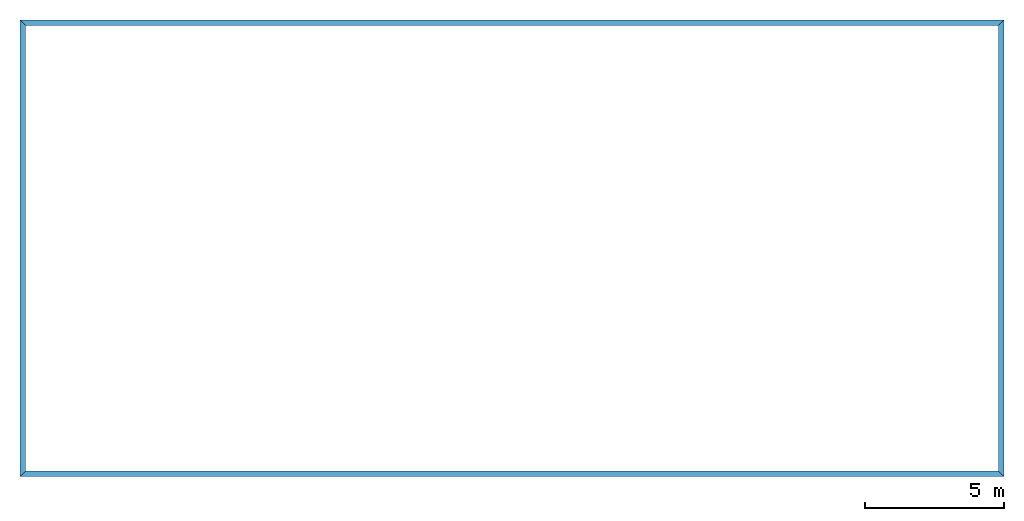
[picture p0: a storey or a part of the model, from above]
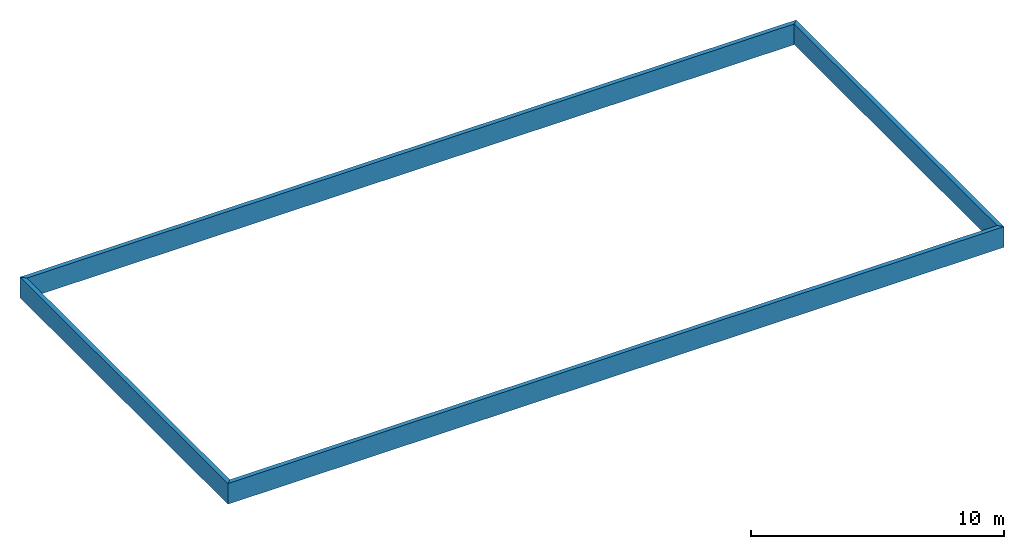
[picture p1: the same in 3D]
Properties of the parts of a building model (IFC2X3)

# File
Description: ViewDefinition [CoordinationView_V2.0], Option [Elements to export: Visible elements (on all stories)], Option [Partial Structure Display: Entire Model], Option [IFC Domain: All], Option [Structural Function: All Elements], Option [Convert Grid elements: On], Option [Convert IFC Annotations and Archicad 2D elements: Off], Option [Convert 2D symbols of Doors and Windows: Off], Option [Export geometries that Participates in Collision Detection only: Off], Option [Split complex elements: Off], Option [Material Preservation: Explode where necessary], Option [Elements in Solid Element Operations: Extruded/revolved], Option [Elements with junctions: Extruded/revolved without junctions], Option [IFC Model position: Survey Point and Project Origin], Option [Curtain Wall export mode: Container Element], Option [Railing export mode: Single Element], Option [Stair export mode: Container Element], Option [Properties To Export: All properties], Option [Space containment: Off], Option [Geometry to type objects: Off], Option [Element Properties: Off], Option [Building Material Properties: Off], Option [Element Parameters: Off], Option [Component Parameters: Off], Option [IFC Base Quantities: Off], Option [Door Window Parameters: On], Option [IFC Space boundaries: Off], Option [Archicad Zone Categories as IFC Space classification data: Off], Option [Element Classifications: Off]
File name: C:\Users\LUCAS\Desktop\FT DCE\IFC\3D PROJET 100.ifc
Time: 2026-07-02T18:41:05
Author: Nom de famille Prénom
Organization: ATELIER D'ARCHITECTURE AIROLDI
Written by: DDS_IFC v3.0
Made in: Graphisoft - Archicad - 28.4.0
Authorization: Nom de famille Prénom

# IfcProject, Construction d'un immeuble de bureaux Agence France Travail
Phase: (provisoire, définitif...)

# IfcSite, Site
RefLatitude: 48, 52, 0, 0; RefLongitude: 2, 20, 0, 0; RefElevation: 149 m

# IfcBuildingStorey (5)
In: Bâtiment
Name | Elevation (m)
R-1 | -3
Toiture | 10.12
Combles | 7.12
RDC | 0
R+1 | 3.56

# IfcBeam: ** COUVERTINE 01 50x5cm 379 x 50 (7)
Material: Métal - Fer
AC_Pset_RenovationAndPhasing - Renovation Status: New
Pset_BeamCommon - IsExternal: no; LoadBearing: yes; Reference: ** COUVERTINE 01 50x5cm 379 x 50
Name | In
3 x PoBA-002 | R+1
4 x PoBA-002 | Combles

# IfcBeam: ** LOGO FT 917 x 1022, PoBA-003
In: R+1
AC_Pset_RenovationAndPhasing - Renovation Status: New
Pset_BeamCommon - IsExternal: no; LoadBearing: yes; Reference: ** LOGO FT 917 x 1022

# IfcBeam: ** LOGO FT petit 448 x 500, PoBA-003
In: R+1
Pset_BeamCommon - IsExternal: no; LoadBearing: yes; Reference: ** LOGO FT petit 448 x 500
AC_Pset_RenovationAndPhasing - Renovation Status: New

# IfcBeam: Acier 50 x 50 (2)
In: Combles
Material: Acier
AC_Pset_RenovationAndPhasing - Renovation Status: New
Pset_BeamCommon - IsExternal: no; LoadBearing: yes; Reference: Acier 50 x 50

# IfcBeam: Aluminium 100 x 150 (8)
In: Toiture
Material: Aluminium
Pset_BeamCommon - IsExternal: no; LoadBearing: yes; Reference: Aluminium 100 x 150
AC_Pset_RenovationAndPhasing - Renovation Status: New

# IfcBeam: Aluminium 100 x 3 (83)
Material: Aluminium
AC_Pset_RenovationAndPhasing - Renovation Status: New
Pset_BeamCommon - IsExternal: no; LoadBearing: yes; Reference: Aluminium 100 x 3
Name | In
4 x PoBA-002 | RDC
79 x PoBA-002 | R+1

# IfcBeam: Aluminium 50 x 50 (3)
In: Combles
Material: Aluminium
AC_Pset_RenovationAndPhasing - Renovation Status: New
Pset_BeamCommon - IsExternal: no; LoadBearing: yes; Reference: Aluminium 50 x 50

# IfcBeam: Aluminium 50 x 75 (10)
In: Toiture
Material: Aluminium
Pset_BeamCommon - IsExternal: no; LoadBearing: yes; Reference: Aluminium 50 x 75
AC_Pset_RenovationAndPhasing - Renovation Status: New

# IfcBeam: Bois massif 80 x 40 (2)
In: R+1
Material: Bois massif
Pset_BeamCommon - IsExternal: no; LoadBearing: yes; Reference: Bois massif 80 x 40
AC_Pset_RenovationAndPhasing - Renovation Status: New

# IfcBeam: Béton 250 x 400 (8)
Material: Béton
AC_Pset_RenovationAndPhasing - Renovation Status: New
Pset_BeamCommon - IsExternal: no; LoadBearing: yes; Reference: Béton 250 x 400
Name | In
6 x PoBA-006 | RDC
2 x PoBA-006 | R+1

# IfcBeam: Béton 250 x 665, PoBA-006
In: RDC
Material: Béton
AC_Pset_RenovationAndPhasing - Renovation Status: New
Pset_BeamCommon - IsExternal: no; LoadBearing: yes; Reference: Béton 250 x 665

# IfcBeam: Métal - Acier 80 x 30, PANNE MULTIBEAM
In: RDC
Material: Métal - Acier
Pset_BeamCommon - IsExternal: no; LoadBearing: yes; Reference: Métal - Acier 80 x 30
AC_Pset_RenovationAndPhasing - Renovation Status: New

# IfcBeam: Métal - Acier 80 x 40 (8)
In: RDC
Material: Métal - Acier
AC_Pset_RenovationAndPhasing - Renovation Status: New
Pset_BeamCommon - IsExternal: no; LoadBearing: yes; Reference: Métal - Acier 80 x 40

# IfcBeam: UAP80 45 x 80 (5)
In: Combles
Material: Acier
AC_Pset_RenovationAndPhasing - Renovation Status: New
Pset_BeamCommon - IsExternal: no; LoadBearing: yes; Reference: UAP80 45 x 80

# IfcBuildingElementPart (288)
Name | In | Material
185 x Acier Galva | RDC | Acier Galva
2 x Finition int - Stratifié | RDC | Finition int - Stratifié
7 x Métal - Zinc | RDC | Métal - Zinc
6 x Métal - Aluminium | RDC | Métal - Aluminium
9 x *MAILLE jacob | RDC | *MAILLE jacob
2 x Finition int - Plaque de plâtre | RDC | Finition int - Plaque de plâtre
Isolation - Laine de verre | RDC | Isolation - Laine de verre
8 x Env. - Sable | R+1 | Env. - Sable
14 x GENERIQUE - ENVIRONNEMENT | R+1 | GENERIQUE - ENVIRONNEMENT
6 x Plastique - PVC | R+1 | Plastique - PVC
8 x Métal - Zinc | R+1 | Métal - Zinc
6 x Env. - Herbe | R+1 | Env. - Herbe
6 x *PLAQUE DE PLATRE - CLOISON | R+1 | *PLAQUE DE PLATRE - CLOISON
3 x *GENERIQUE - ISOLATION INT | R+1 | *GENERIQUE - ISOLATION INT
3 x Isolation - Laine de verre | R+1 | Isolation - Laine de verre
6 x Finition int - Plaque de plâtre | R+1 | Finition int - Plaque de plâtre
3 x Finition int - Stratifié | R+1 | Finition int - Stratifié
3 x Métal - Aluminium | R+1 | Métal - Aluminium
2 x *GENERIQUE - ENDUIT EXT | Combles | *GENERIQUE - ENDUIT EXT
2 x *GENERIQUE - MAÇONNERIE | Combles | *GENERIQUE - MAÇONNERIE
2 x *MÉTAL- BARDAGE | Combles | *MÉTAL- BARDAGE
2 x Finition int - Enduit plâtre | Combles | Finition int - Enduit plâtre
2 x Divers - Vide faux plafond | Combles | Divers - Vide faux plafond

# IfcBuildingElementProxy: IfcBuildingElementProxy (5)
In: RDC
Material: Béton
AC_Pset_RenovationAndPhasing - Renovation Status: New
Name
VOLEE-008
VOLEE-010
PALIER-004
PALIER-003
VOLEE-009

# IfcBuildingElementProxy: Lavabo 27 (4)
AC_Pset_RenovationAndPhasing - Renovation Status: New
Name | In
2 x PLACE STATIONNEMENT PMR | RDC
VIDOIR | RDC
PLACE STATIONNEMENT PMR | R+1

# IfcBuildingElementProxy: Plan multi vasques 27 (2)
AC_Pset_RenovationAndPhasing - Renovation Status: New
Name | In
PLACE STATIONNEMENT PMR | RDC
PLACE STATIONNEMENT PMR | R+1

# IfcBuildingElementProxy: Porte-serviettes 03 27 (3)
AC_Pset_RenovationAndPhasing - Renovation Status: New
Name | In
2 x barre d'appui | RDC
barre d'appui | R+1

# IfcBuildingElementProxy: TAPIS ENCASTRÉ (5)
AC_Pset_RenovationAndPhasing - Renovation Status: New
Name | In
2 x LAVABO | RDC
3 x CLOUS PODO | R+1

# IfcBuildingElementProxy: Type d'escalier, ESC-004
In: RDC
AC_Pset_RenovationAndPhasing - Renovation Status: New

# IfcBuildingElementProxy: Type de garde-corps (5)
In: RDC
Name | Renovation Status
3 x RAMPE-004 | New
RAMPE-003 | Existing
RAMPE-003 | New

# IfcBuildingElementProxy: WC 27 (3)
AC_Pset_RenovationAndPhasing - Renovation Status: New
Name | In
PLACE STATIONNEMENT PMR | RDC
2 x PLACE STATIONNEMENT PMR | R+1

# IfcColumn: Aluminium 100 x 100 (8)
In: Toiture
Material: Aluminium
AC_Pset_RenovationAndPhasing - Renovation Status: New
Pset_ColumnCommon - LoadBearing: yes; Reference: Aluminium 100 x 100

# IfcColumn: Aluminium 100 x 3 (78)
Material: Aluminium
AC_Pset_RenovationAndPhasing - Renovation Status: New
Pset_ColumnCommon - LoadBearing: yes; Reference: Aluminium 100 x 3
Name | In
16 x PotB-005 | RDC
62 x PotB-005 | R+1

# IfcColumn: Aluminium 20 x 50 (3)
In: R+1
Material: Aluminium
AC_Pset_RenovationAndPhasing - Renovation Status: New
Pset_ColumnCommon - LoadBearing: yes; Reference: Aluminium 20 x 50

# IfcColumn: Aluminium 50 x 20 (2)
In: R+1
Material: Aluminium
Pset_ColumnCommon - LoadBearing: yes; Reference: Aluminium 50 x 20
AC_Pset_RenovationAndPhasing - Renovation Status: New

# IfcColumn: Aluminium 50 x 50 (3)
In: R+1
Material: Aluminium
AC_Pset_RenovationAndPhasing - Renovation Status: New
Pset_ColumnCommon - LoadBearing: yes; Reference: Aluminium 50 x 50

# IfcColumn: Bois - Massif 01 40 x 80 (28)
In: R+1
Material: Bois - Massif 01
AC_Pset_RenovationAndPhasing - Renovation Status: New
Pset_ColumnCommon - LoadBearing: yes; Reference: Bois - Massif 01 40 x 80

# IfcColumn: Béton 250 x 250 (16)
Material: Béton
AC_Pset_RenovationAndPhasing - Renovation Status: New
Pset_ColumnCommon - LoadBearing: yes; Reference: Béton 250 x 250
Name | In
8 x PotB-005 | RDC
8 x PotB-005 | R+1

# IfcColumn: Béton 300 x 300, PotB-008
In: R+1
Material: Béton
AC_Pset_RenovationAndPhasing - Renovation Status: New
Pset_ColumnCommon - LoadBearing: yes; Reference: Béton 300 x 300

# IfcColumn: Béton D250 (2)
In: RDC
Material: Béton
AC_Pset_RenovationAndPhasing - Renovation Status: New
Pset_ColumnCommon - LoadBearing: yes; Reference: Béton D250

# IfcColumn: Métal - Acier 20 x 20 (86)
In: RDC
Material: Métal - Acier
AC_Pset_RenovationAndPhasing - Renovation Status: New
Pset_ColumnCommon - LoadBearing: yes; Reference: Métal - Acier 20 x 20

# IfcColumn: Métal - Acier 30 x 80 (6)
In: RDC
Material: Métal - Acier
AC_Pset_RenovationAndPhasing - Renovation Status: New
Pset_ColumnCommon - LoadBearing: yes; Reference: Métal - Acier 30 x 80

# IfcColumn: Métal - Acier 40 x 80 (13)
In: RDC
Material: Métal - Acier
AC_Pset_RenovationAndPhasing - Renovation Status: New
Pset_ColumnCommon - LoadBearing: yes; Reference: Métal - Acier 40 x 80

# IfcCovering: Tôle profilée 27 (67)
Material: Métal - Acier
AC_Pset_RenovationAndPhasing - Renovation Status: New
Name | In
13 x PLACE STATIONNEMENT PMR | RDC
54 x PLACE STATIONNEMENT PMR | R+1

# IfcDiscreteAccessory: Texte 3D 27 (4)
In: R+1
AC_Pset_RenovationAndPhasing - Renovation Status: New

# IfcDiscreteAccessory: Tuyau descente 27 (4)
In: RDC
AC_Pset_RenovationAndPhasing - Renovation Status: New

# IfcDistributionElement: WC pour handicapés 27 (3)
AC_Pset_RenovationAndPhasing - Renovation Status: New
Name | In
2 x WC PMR | RDC
WC PMR | R+1

# IfcDoor: Porte 27 (2)
In: RDC
Type - OperationType: SINGLE_SWING_LEFT; ParameterTakesPrecedence: no; Sizeable: no
Type - Door Lining Properties - LiningDepth: 0.05 m; LiningThickness: 0.05 m; LiningOffset: -0.05 m
Type - Door Panel Properties - Panel 1 - PanelDepth: 0.04 m; PanelOperation: SWINGING; PanelWidth: 1; PanelPosition: MIDDLE
OverallHeight: 2.1 m; OverallWidth: 1 m
Pset_DoorCommon - ThermalTransmittance: 0; IsExternal: no
AC_Pset_RenovationAndPhasing - Renovation Status: New
Name
Pi.05
Pi.04 REI30 + FP

# IfcDoor: Porte 27, Pi.04 REI30
In: RDC
Type - OperationType: SINGLE_SWING_LEFT; ParameterTakesPrecedence: no; Sizeable: no
Type - Door Lining Properties - LiningDepth: 0.05 m; LiningThickness: 0.05 m; LiningOffset: 0 m
Type - Door Panel Properties - Panel 1 - PanelDepth: 0.04 m; PanelOperation: SWINGING; PanelWidth: 1; PanelPosition: MIDDLE
OverallHeight: 2.1 m; OverallWidth: 1 m
Pset_DoorCommon - ThermalTransmittance: 0; IsExternal: no
AC_Pset_RenovationAndPhasing - Renovation Status: New

# IfcDoor: Porte 27 (4)
Type - OperationType: SINGLE_SWING_LEFT; ParameterTakesPrecedence: no; Sizeable: no
Type - Door Lining Properties - LiningDepth: 0.05 m; LiningThickness: 0.05 m; LiningOffset: 0.024 m
Type - Door Panel Properties - Panel 1 - PanelDepth: 0.04 m; PanelOperation: SWINGING; PanelWidth: 1; PanelPosition: MIDDLE
OverallHeight: 2.1 m; OverallWidth: 1 m
Pset_DoorCommon - ThermalTransmittance: 0; IsExternal: no
AC_Pset_RenovationAndPhasing - Renovation Status: New
Name | In
2 x Pi.05 | RDC
2 x Pi.05 | R+1

# IfcDoor: Porte 27, Pi.04 REI30 + FP
In: R+1
Type - OperationType: SINGLE_SWING_LEFT; ParameterTakesPrecedence: no; Sizeable: no
Type - Door Lining Properties - LiningDepth: 0.05 m; LiningThickness: 0.05 m; LiningOffset: 0.05 m
Type - Door Panel Properties - Panel 1 - PanelDepth: 0.04 m; PanelOperation: SWINGING; PanelWidth: 1; PanelPosition: MIDDLE
OverallHeight: 2.1 m; OverallWidth: 1 m
Pset_DoorCommon - ThermalTransmittance: 0; IsExternal: no
AC_Pset_RenovationAndPhasing - Renovation Status: New

# IfcDoor: Porte 27, PE.02
In: RDC
Type - OperationType: SINGLE_SWING_LEFT; ParameterTakesPrecedence: no; Sizeable: no
Type - Door Lining Properties - LiningDepth: 0.12 m; LiningThickness: 0.05 m; LiningOffset: -0.002 m; CasingThickness: 0.05 m; CasingDepth: 0.019 m
Type - Door Panel Properties - Panel 1 - PanelDepth: 0.04 m; PanelOperation: SWINGING; PanelWidth: 1; PanelPosition: MIDDLE
OverallHeight: 2.5 m; OverallWidth: 1.05 m
Pset_DoorCommon - ThermalTransmittance: 0; GlazingAreaFraction: 1.7301; IsExternal: yes
AC_Pset_RenovationAndPhasing - Renovation Status: New

# IfcDoor: Porte 27, PE.03
In: RDC
Type - OperationType: SINGLE_SWING_LEFT; ParameterTakesPrecedence: no; Sizeable: no
Type - Door Lining Properties - LiningDepth: 0.16 m; LiningThickness: 0.05 m; LiningOffset: -0.002 m; CasingThickness: 0.05 m; CasingDepth: 0.019 m
Type - Door Panel Properties - Panel 1 - PanelDepth: 0.04 m; PanelOperation: SWINGING; PanelWidth: 1; PanelPosition: MIDDLE
OverallHeight: 2.5 m; OverallWidth: 1.05 m
Pset_DoorCommon - ThermalTransmittance: 0; GlazingAreaFraction: 1.7301; IsExternal: yes
AC_Pset_RenovationAndPhasing - Renovation Status: New

# IfcDoor: Porte 27 (10)
Type - OperationType: SINGLE_SWING_LEFT; ParameterTakesPrecedence: no; Sizeable: no
Type - Door Lining Properties - LiningThickness: 0.05 m
Type - Door Panel Properties - Panel 1 - PanelDepth: 0.04 m; PanelOperation: SWINGING; PanelWidth: 1; PanelPosition: MIDDLE
OverallHeight: 2.1 m; OverallWidth: 1 m
Pset_DoorCommon - ThermalTransmittance: 0; IsExternal: no
AC_Pset_RenovationAndPhasing - Renovation Status: New
Name | In
2 x Pi.03 | RDC
2 x Pi.01 | RDC
6 x Pi.01 | R+1

# IfcDoor: Porte 27 (2)
Type - OperationType: SINGLE_SWING_RIGHT; ParameterTakesPrecedence: no; Sizeable: no
Type - Door Lining Properties - LiningDepth: 0.05 m; LiningThickness: 0.05 m; LiningOffset: -0.074 m
Type - Door Panel Properties - Panel 1 - PanelDepth: 0.04 m; PanelOperation: SWINGING; PanelWidth: 1; PanelPosition: MIDDLE
OverallHeight: 2.1 m; OverallWidth: 1 m
Pset_DoorCommon - ThermalTransmittance: 0; IsExternal: no
AC_Pset_RenovationAndPhasing - Renovation Status: New
Name | In
Pi.06 | RDC
Pi.06 | R+1

# IfcDoor: Porte 27 (4)
Type - OperationType: SINGLE_SWING_RIGHT; ParameterTakesPrecedence: no; Sizeable: no
Type - Door Lining Properties - LiningDepth: 0.05 m; LiningThickness: 0.05 m; LiningOffset: 0.024 m
Type - Door Panel Properties - Panel 1 - PanelDepth: 0.04 m; PanelOperation: SWINGING; PanelWidth: 1; PanelPosition: MIDDLE
OverallHeight: 2.1 m; OverallWidth: 1 m
Pset_DoorCommon - ThermalTransmittance: 0; IsExternal: no
AC_Pset_RenovationAndPhasing - Renovation Status: New
Name | In
Pi.06 | RDC
Pi.05 | R+1
2 x Pi.06 | R+1

# IfcDoor: Porte 27, Pi.01
In: R+1
Type - OperationType: SINGLE_SWING_RIGHT; ParameterTakesPrecedence: no; Sizeable: no
Type - Door Lining Properties - LiningDepth: 0.05 m; LiningThickness: 0.05 m; LiningOffset: 0.03 m
Type - Door Panel Properties - Panel 1 - PanelDepth: 0.04 m; PanelOperation: SWINGING; PanelWidth: 1; PanelPosition: MIDDLE
OverallHeight: 2.1 m; OverallWidth: 1 m
Pset_DoorCommon - ThermalTransmittance: 0; IsExternal: no
AC_Pset_RenovationAndPhasing - Renovation Status: New

# IfcDoor: Porte 27 (10)
Type - OperationType: SINGLE_SWING_RIGHT; ParameterTakesPrecedence: no; Sizeable: no
Type - Door Lining Properties - LiningThickness: 0.05 m
Type - Door Panel Properties - Panel 1 - PanelDepth: 0.04 m; PanelOperation: SWINGING; PanelWidth: 1; PanelPosition: MIDDLE
OverallHeight: 2.1 m; OverallWidth: 1 m
Pset_DoorCommon - ThermalTransmittance: 0; IsExternal: no
AC_Pset_RenovationAndPhasing - Renovation Status: New
Name | In
5 x Pi.01 | RDC
5 x Pi.01 | R+1

# IfcDoor: Porte avec imposte 27, Pi.01
In: RDC
Type - OperationType: SINGLE_SWING_RIGHT; ParameterTakesPrecedence: no; Sizeable: no
Type - Door Lining Properties - LiningThickness: 0.05 m; TransomThickness: 0.04 m; TransomOffset: 1.99 m
Type - Door Panel Properties - Panel 1 - PanelDepth: 0.04 m; PanelOperation: SWINGING; PanelWidth: 1; PanelPosition: MIDDLE
OverallHeight: 2.6 m; OverallWidth: 1 m
Pset_DoorCommon - ThermalTransmittance: 0; GlazingAreaFraction: 0.4743; IsExternal: no
AC_Pset_RenovationAndPhasing - Renovation Status: New

# IfcDoor: Porte avec tierce vitrée côté 2 27, PE.04
In: R+1
Type - OperationType: SINGLE_SWING_LEFT; ParameterTakesPrecedence: no; Sizeable: no
Type - Door Panel Properties - Panel 1 - PanelDepth: 0.04 m; PanelOperation: SWINGING; PanelWidth: 1; PanelPosition: MIDDLE
OverallHeight: 2.15 m; OverallWidth: 1.4 m
Pset_DoorCommon - ThermalTransmittance: 0; GlazingAreaFraction: 1.92314; IsExternal: yes
AC_Pset_RenovationAndPhasing - Renovation Status: New

# IfcDoor: Porte avec tierce vitrée côté 2 27 (2)
In: R+1
Type - OperationType: SINGLE_SWING_RIGHT; ParameterTakesPrecedence: no; Sizeable: no
Type - Door Panel Properties - Panel 1 - PanelDepth: 0.04 m; PanelOperation: SWINGING; PanelWidth: 1; PanelPosition: MIDDLE
OverallWidth: 1.4 m
Pset_DoorCommon - ThermalTransmittance: 0
AC_Pset_RenovationAndPhasing - Renovation Status: New
Name | OverallHeight (m) | GlazingAreaFraction | IsExternal
Pi.07 | 2.1 | 0.397946 | no
PE.04 | 2.15 | 1.92314 | yes

# IfcDoor: Porte double 27, Pi.03
In: RDC
Type - OperationType: DOUBLE_DOOR_SINGLE_SWING; ParameterTakesPrecedence: no; Sizeable: no
Type - Door Lining Properties - LiningDepth: 0.05 m; LiningThickness: 0.05 m; LiningOffset: -0.05 m
Type - Door Panel Properties - Panel 1 - PanelDepth: 0.04 m; PanelOperation: SWINGING; PanelWidth: 0.397187; PanelPosition: LEFT
Type - Door Panel Properties - Panel 2 - PanelDepth: 0.04 m; PanelOperation: SWINGING; PanelWidth: 0.602813; PanelPosition: RIGHT
OverallHeight: 2.1 m; OverallWidth: 1.563 m
Pset_DoorCommon - ThermalTransmittance: 0; IsExternal: no
AC_Pset_RenovationAndPhasing - Renovation Status: New

# IfcDoor: Porte double 27, Pi.03
In: RDC
Type - OperationType: DOUBLE_DOOR_SINGLE_SWING; ParameterTakesPrecedence: no; Sizeable: no
Type - Door Lining Properties - LiningDepth: 0.05 m; LiningThickness: 0.05 m; LiningOffset: -0.05 m
Type - Door Panel Properties - Panel 1 - PanelDepth: 0.04 m; PanelOperation: SWINGING; PanelWidth: 0.397591; PanelPosition: RIGHT
Type - Door Panel Properties - Panel 2 - PanelDepth: 0.04 m; PanelOperation: SWINGING; PanelWidth: 0.602409; PanelPosition: LEFT
OverallHeight: 2.1 m; OverallWidth: 1.564 m
Pset_DoorCommon - ThermalTransmittance: 0; IsExternal: no
AC_Pset_RenovationAndPhasing - Renovation Status: New

# IfcDoor: Porte double 27, Pi.02
In: RDC
Type - OperationType: DOUBLE_DOOR_SINGLE_SWING; ParameterTakesPrecedence: no; Sizeable: no
Type - Door Lining Properties - LiningDepth: 0.05 m; LiningThickness: 0.05 m; LiningOffset: 0 m
Type - Door Panel Properties - Panel 1 - PanelDepth: 0.04 m; PanelOperation: SWINGING; PanelWidth: 0.370629; PanelPosition: RIGHT
Type - Door Panel Properties - Panel 2 - PanelDepth: 0.04 m; PanelOperation: SWINGING; PanelWidth: 0.629371; PanelPosition: LEFT
OverallHeight: 2.1 m; OverallWidth: 1.5 m
Pset_DoorCommon - ThermalTransmittance: 0; IsExternal: no
AC_Pset_RenovationAndPhasing - Renovation Status: New

# IfcDoor: Porte double 27, Pi.03
In: R+1
Type - OperationType: DOUBLE_DOOR_SINGLE_SWING; ParameterTakesPrecedence: no; Sizeable: no
Type - Door Lining Properties - LiningDepth: 0.05 m; LiningThickness: 0.05 m; LiningOffset: 0.03 m
Type - Door Panel Properties - Panel 1 - PanelDepth: 0.04 m; PanelOperation: SWINGING; PanelWidth: 0.395973; PanelPosition: RIGHT
Type - Door Panel Properties - Panel 2 - PanelDepth: 0.04 m; PanelOperation: SWINGING; PanelWidth: 0.604027; PanelPosition: LEFT
OverallHeight: 2.1 m; OverallWidth: 1.56 m
Pset_DoorCommon - ThermalTransmittance: 0; IsExternal: no
AC_Pset_RenovationAndPhasing - Renovation Status: New

# IfcDoor: Porte double 27, Pi.03
In: R+1
Type - OperationType: DOUBLE_DOOR_SINGLE_SWING; ParameterTakesPrecedence: no; Sizeable: no
Type - Door Lining Properties - LiningDepth: 0.05 m; LiningThickness: 0.05 m; LiningOffset: 0.03 m
Type - Door Panel Properties - Panel 1 - PanelDepth: 0.04 m; PanelOperation: SWINGING; PanelWidth: 0.397591; PanelPosition: LEFT
Type - Door Panel Properties - Panel 2 - PanelDepth: 0.04 m; PanelOperation: SWINGING; PanelWidth: 0.602409; PanelPosition: RIGHT
OverallHeight: 2.1 m; OverallWidth: 1.564 m
Pset_DoorCommon - ThermalTransmittance: 0; IsExternal: no
AC_Pset_RenovationAndPhasing - Renovation Status: New

# IfcDoor: Porte double 27, PE.01
In: RDC
Type - OperationType: DOUBLE_DOOR_SINGLE_SWING; ParameterTakesPrecedence: no; Sizeable: no
Type - Door Lining Properties - LiningDepth: 0.16 m; LiningThickness: 0.05 m; LiningOffset: 0.168 m; CasingThickness: 0.05 m; CasingDepth: 0.07 m
Type - Door Panel Properties - Panel 1 - PanelDepth: 0.04 m; PanelOperation: SWINGING; PanelWidth: 0.324324; PanelPosition: RIGHT
Type - Door Panel Properties - Panel 2 - PanelDepth: 0.04 m; PanelOperation: SWINGING; PanelWidth: 0.675676; PanelPosition: LEFT
OverallHeight: 2.5 m; OverallWidth: 1.6 m
Pset_DoorCommon - ThermalTransmittance: 0; GlazingAreaFraction: 2.628; IsExternal: yes
AC_Pset_RenovationAndPhasing - Renovation Status: New

# IfcDoor: Porte double avec 2 fixes latéraux, imposte 27, PC.01a
In: RDC
Type - OperationType: USERDEFINED; ParameterTakesPrecedence: no; Sizeable: no
OverallHeight: 2.6 m; OverallWidth: 2.86158 m
Pset_DoorCommon - ThermalTransmittance: 0; GlazingAreaFraction: 5.61587; IsExternal: no
AC_Pset_RenovationAndPhasing - Renovation Status: New

# IfcFurnishingElement: Armoire 02 27 (2)
In: R+1
AC_Pset_RenovationAndPhasing - Renovation Status: New

# IfcFurnishingElement: Bac à terre 27, PLACE STATIONNEMENT PMR
In: R+1
AC_Pset_RenovationAndPhasing - Renovation Status: New

# IfcFurnishingElement: Canapé 01 27, WC PMR
In: R+1
AC_Pset_RenovationAndPhasing - Renovation Status: New

# IfcFurnishingElement: Casiers 27, WC PMR
In: R+1
AC_Pset_RenovationAndPhasing - Renovation Status: New

# IfcFurnishingElement: Chaise de conférence 1 27 (51)
AC_Pset_RenovationAndPhasing - Renovation Status: New
Name | In
39 x PLACE STATIONNEMENT PMR | RDC
12 x PLACE STATIONNEMENT PMR | R+1

# IfcFurnishingElement: Meuble bas bloc 27 (5)
In: R+1
AC_Pset_RenovationAndPhasing - Renovation Status: New

# IfcFurnishingElement: Poste de travail de bureau unique 27 (45)
AC_Pset_RenovationAndPhasing - Renovation Status: New
Name | In
18 x PLACE STATIONNEMENT PMR | RDC
27 x PLACE STATIONNEMENT PMR | R+1

# IfcFurnishingElement: Réfrigérateur haut 27 (3)
In: R+1
AC_Pset_RenovationAndPhasing - Renovation Status: New

# IfcFurnishingElement: Table haute rectangulaire 27 (2)
In: RDC
AC_Pset_RenovationAndPhasing - Renovation Status: New

# IfcFurnishingElement: Table haute ronde 27 (12)
AC_Pset_RenovationAndPhasing - Renovation Status: New
Name | In
2 x PLACE STATIONNEMENT PMR | RDC
10 x PLACE STATIONNEMENT PMR | R+1

# IfcSlab: *Dalle portée hourdi isolé + finition 220, DC_BA_Isol-005
In: RDC
Type - PredefinedType: FLOOR
Material: *FINITION SOL INT - sol souple 0.02 m, *GENERIQUE - MAÇONNERIE 0.05 m, *GENERIQUE - ISOLATION PLANCHER 0.15 m
Pset_SlabCommon - IsExternal: no; LoadBearing: yes
AC_Pset_RenovationAndPhasing - Renovation Status: New

# IfcSlab: *MAILLE jacob 30, DC_BA_Isol-005
In: R+1
Type - PredefinedType: FLOOR
Material: *MAILLE jacob 0.03 m
AC_Pset_RenovationAndPhasing - Renovation Status: New
Pset_SlabCommon - IsExternal: no; LoadBearing: yes

# IfcSlab: *Plafond 1/2 STIL 61 (8)
Type - PredefinedType: FLOOR
Material: *OSSATURE PLACO 0.048 m, *PLAQUE DE PLATRE - PLAFOND 0.013 m
AC_Pset_RenovationAndPhasing - Renovation Status: New
Pset_SlabCommon - IsExternal: no; LoadBearing: no
Name | In
Plafond métallique acoustique perforé | RDC
4 x Plafond acoustique démontable | RDC
Plafond acoustique démontable 1ère volée escalier | RDC
Plafond acoustique démontable WC public RDC | RDC
Plafond acoustique démontable | R+1

# IfcSlab: *Plancher béton+CHAPE+FINITION 290, DC_BA_Isol-004
In: RDC
Type - PredefinedType: FLOOR
Material: *FINITION SOL INT - sol souple 0.02 m, *CHAPE 0.07 m, *GENERIQUE - MAÇONNERIE 0.2 m
AC_Pset_RenovationAndPhasing - Renovation Status: Existing
Pset_SlabCommon - IsExternal: no; LoadBearing: yes

# IfcSlab: *Plancher béton+FINITION 220 (2)
Type - PredefinedType: FLOOR
Material: *FINITION SOL INT - sol souple 0.02 m, *GENERIQUE - MAÇONNERIE 0.2 m
Pset_SlabCommon - IsExternal: no; LoadBearing: yes
AC_Pset_RenovationAndPhasing - Renovation Status: New
Name | In
DC_BA_Isol-005 | R+1
DC_BA_Isol-005 | Combles

# IfcSlab: *Toiture MEMBRANE PVC 355, Toit-08
In: Toiture
Type - PredefinedType: ROOF
Material: *ÉTANCHÉITÉ 0.015 m, *GENERIQUE - ISOLATION PLANCHER 0.14 m, Béton 0.2 m
Pset_SlabCommon - IsExternal: yes; LoadBearing: no
AC_Pset_RenovationAndPhasing - Renovation Status: New

# IfcSlab: *Toiture TERRASSE ETANCHÉE graviers 335, DC_BA_Isol-005
In: R+1
Type - PredefinedType: FLOOR
Material: *GRAVIERS 0.05 m, *ÉTANCHÉITÉ 0.015 m, *GENERIQUE - ISOLATION PLANCHER 0.07 m, Béton 0.2 m
AC_Pset_RenovationAndPhasing - Renovation Status: New
Pset_SlabCommon - IsExternal: no; LoadBearing: yes

# IfcSlab: *Toiture TERRASSE ETANCHÉE sur plots 485, DC_BA_Isol-005
In: R+1
Type - PredefinedType: FLOOR
Material: Béton préfabriqué 0.05 m, Vide faux plafond 0.15 m, *ÉTANCHÉITÉ 0.015 m, *GENERIQUE - ISOLATION PLANCHER 0.07 m, Béton 0.2 m
Pset_SlabCommon - IsExternal: no; LoadBearing: yes
AC_Pset_RenovationAndPhasing - Renovation Status: New

# IfcSlab: *Toiture TUILES 150 (7)
Type - PredefinedType: ROOF
Material: *TUILES, *BOIS - LATTAGE OU LITEAUX, *BOIS SOLIVAGE
AC_Pset_RenovationAndPhasing - Renovation Status: Existing
Pset_SlabCommon - IsExternal: yes; LoadBearing: no
Name | In
Toit-07 | R+1
2 x Toit-07 | Combles
3 x Toit-07 | Toiture
Toit-08 | Toiture

# IfcSlab: Asphalte 200, DC_BA_Isol-005
In: RDC
Type - PredefinedType: FLOOR
Material: Asphalte 0.2 m
AC_Pset_RenovationAndPhasing - Renovation Status: New
Pset_SlabCommon - IsExternal: no; LoadBearing: yes

# IfcSlab: Eau 1500, Bassin rétention EP
In: RDC
Type - PredefinedType: FLOOR
Material: Eau 1.5 m
Pset_SlabCommon - IsExternal: no; LoadBearing: yes
AC_Pset_RenovationAndPhasing - Renovation Status: New

# IfcSlab: Eau 200, Bassin rétention EP
In: RDC
Type - PredefinedType: FLOOR
Material: Eau 0.2 m
AC_Pset_RenovationAndPhasing - Renovation Status: New
Pset_SlabCommon - IsExternal: no; LoadBearing: yes

# IfcSlab: Eau 870, Bassin rétention EP
In: RDC
Type - PredefinedType: FLOOR
Material: Eau 0.87 m
AC_Pset_RenovationAndPhasing - Renovation Status: New
Pset_SlabCommon - IsExternal: no; LoadBearing: yes

# IfcSlab: Plastique 50 (2)
In: R+1
Type - PredefinedType: ROOF
Material: Plastique 0.0498779 m
AC_Pset_RenovationAndPhasing - Renovation Status: New
Pset_SlabCommon - IsExternal: yes; LoadBearing: no

# IfcTransportElement: Ascenseur 27, WC PMR
In: RDC
AC_Pset_RenovationAndPhasing - Renovation Status: New

# IfcWall: *Cloison 72 74 (4)
AC_Pset_RenovationAndPhasing - Renovation Status: New
Name | In | IsExternal = LoadBearing
Cloisons ép. 72mm | RDC | yes
3 x Cloisons ép. 72mm | R+1 | no

# IfcWall: *Cloison 98 100 (3)
In: R+1
AC_Pset_RenovationAndPhasing - Renovation Status: New
Pset_WallCommon - IsExternal: no; LoadBearing: no

# IfcWall: *MACONNERIE BARDAGE METAL Acrotère 318 (2)
In: Combles
AC_Pset_RenovationAndPhasing - Renovation Status: New
Pset_WallCommon - IsExternal: yes; LoadBearing: yes

# IfcWall: *PLAQUE DE PLATRE - CLOISON 13, Plaque de plâtre collée
In: R+1
Material: *PLAQUE DE PLATRE - CLOISON
AC_Pset_RenovationAndPhasing - Renovation Status: New
Pset_WallCommon - IsExternal: no; LoadBearing: no

# IfcWallStandardCase: *Cloison 72 74 (36)
Material: Finition int - Plaque de plâtre 0.013 m, Isolation - Laine de verre 0.048 m, Finition int - Plaque de plâtre 0.013 m
AC_Pset_RenovationAndPhasing - Renovation Status: New
Name | In | IsExternal = LoadBearing
24 x Cloisons ép. 72mm | RDC | yes
Cloisons ép. 72mm | RDC | no
11 x Cloisons ép. 72mm | R+1 | no

# IfcWallStandardCase: *Cloison 98 100 (11)
Material: *PLAQUE DE PLATRE - CLOISON 0.026 m, *GENERIQUE - ISOLATION INT 0.048 m, *PLAQUE DE PLATRE - CLOISON 0.026 m
AC_Pset_RenovationAndPhasing - Renovation Status: New
Name | In | IsExternal = LoadBearing
7 x Cloison ép.10 - CF1h | RDC | no
Cloison ép.10 - CF1h | RDC | yes
3 x Cloison ép.10 - CF1h | R+1 | no

# IfcWallStandardCase: *GENERIQUE - MAÇONNERIE 200 (2)
Material: *GENERIQUE - MAÇONNERIE 0.2 m
AC_Pset_RenovationAndPhasing - Renovation Status: New
Pset_WallCommon - IsExternal: yes; LoadBearing: yes
Name | In
MC_AGL_Ext-063 | RDC
MC_AGL_Ext-063 | R+1

# IfcWallStandardCase: *GENERIQUE - MAÇONNERIE 5 (62)
In: R+1
Material: *GENERIQUE - MAÇONNERIE 0.005 m
AC_Pset_RenovationAndPhasing - Renovation Status: New
Pset_WallCommon - IsExternal: yes; LoadBearing: yes

# IfcWallStandardCase: *MACONNERIE BARDAGE METAL Acrotère 318 (5)
Material: *MÉTAL- BARDAGE 0.04 m, Divers - Vide faux plafond 0.05 m, Finition int - Enduit plâtre 0.01 m, *GENERIQUE - MAÇONNERIE 0.2 m, *GENERIQUE - ENDUIT EXT 0.018 m
AC_Pset_RenovationAndPhasing - Renovation Status: New
Pset_WallCommon - IsExternal: yes; LoadBearing: yes
Name | In
3 x Mur maçonné + ITI + véture métallique | R+1
2 x Mur maçonné + ITI + véture métallique | Combles

# IfcWallStandardCase: *MACONNERIE ITI BARDAGE METAL 478 (8)
Material: *MÉTAL- BARDAGE 0.04 m, Divers - Vide faux plafond 0.05 m, Finition int - Enduit plâtre 0.01 m, *GENERIQUE - MAÇONNERIE 0.2 m, Finition int - Enduit plâtre 0.01 m, Vide pour liteaux 0.01 m, *GENERIQUE - ISOLATION PLANCHER 0.14 m, *PLAQUE DE PLATRE - DOUBLAGE 0.018 m
AC_Pset_RenovationAndPhasing - Renovation Status: New
Pset_WallCommon - IsExternal: yes; LoadBearing: yes
Name | In
4 x Mur maçonné + ITI + véture métallique | RDC
4 x Mur maçonné + ITI + véture métallique | R+1

# IfcWallStandardCase: *MAILLE jacob 20 (2)
In: R+1
Material: *MAILLE jacob 0.02 m
AC_Pset_RenovationAndPhasing - Renovation Status: New
Pset_WallCommon - IsExternal: no; LoadBearing: no

# IfcWallStandardCase: *Mur ENDUIT 1 face 220 (12)
Material: *GENERIQUE - ENDUIT EXT 0.02 m, *GENERIQUE - MAÇONNERIE 0.2 m
Pset_WallCommon - IsExternal: yes; LoadBearing: yes
Name | In | Renovation Status
MC_AGL_Ext-052 | RDC | Existing
MC_AGL_Ext-053 | RDC | Existing
MC_AGL_Ext-051 | RDC | Existing
MC_AGL_Ext-054 | RDC | Existing
MC_AGL_Ext-060 | RDC | New
MC_AGL_Ext-063 | RDC | New
MC_AGL_Ext-061 | RDC | New
MC_AGL_Ext-062 | RDC | New
MC_AGL_Ext-058 | R+1 | New
MC_AGL_Ext-060 | R+1 | New
MC_AGL_Ext-059 | R+1 | New
MC_AGL_Ext-061 | R+1 | New

# IfcWallStandardCase: *Mur MITI 36 353 (154)
Material: *GENERIQUE - ENDUIT EXT 0.02 m, *GENERIQUE - MAÇONNERIE 0.2 m, *GENERIQUE - ISOLATION INT 0.12 m, *PLAQUE DE PLATRE - DOUBLAGE 0.013 m
AC_Pset_RenovationAndPhasing - Renovation Status: Existing
Pset_WallCommon - IsExternal: yes; LoadBearing: yes
Name | In
MC_AGL_Ext-017 | RDC
MC_AGL_Ext-018 | RDC
MC_AGL_Ext-019 | RDC
MC_AGL_Ext-020 | RDC
MC_AGL_Ext-021 | RDC
MC_AGL_Ext-022 | RDC
MC_AGL_Ext-023 | RDC
MC_AGL_Ext-024 | RDC
MC_AGL_Ext-025 | RDC
MC_AGL_Ext-026 | RDC
MC_AGL_Ext-027 | RDC
MC_AGL_Ext-028 | RDC
MC_AGL_Ext-029 | RDC
MC_AGL_Ext-030 | RDC
MC_AGL_Ext-031 | RDC
MC_AGL_Ext-032 | RDC
MC_AGL_Ext-033 | RDC
MC_AGL_Ext-034 | RDC
MC_AGL_Ext-037 | RDC
MC_AGL_Ext-036 | RDC
MC_AGL_Ext-035 | RDC
MC_AGL_Ext-039 | RDC
MC_AGL_Ext-040 | RDC
MC_AGL_Ext-041 | RDC
MC_AGL_Ext-042 | RDC
MC_AGL_Ext-043 | RDC
MC_AGL_Ext-044 | RDC
2 x MC_AGL_Ext-045 | RDC
2 x MC_AGL_Ext-046 | RDC
2 x MC_AGL_Ext-047 | RDC
2 x MC_AGL_Ext-048 | RDC
2 x MC_AGL_Ext-049 | RDC
2 x MC_AGL_Ext-050 | RDC
2 x MC_AGL_Ext-051 | RDC
2 x MC_AGL_Ext-052 | RDC
2 x MC_AGL_Ext-053 | RDC
2 x MC_AGL_Ext-054 | RDC
2 x MC_AGL_Ext-055 | RDC
2 x MC_AGL_Ext-056 | RDC
2 x MC_AGL_Ext-057 | RDC
4 x MC_AGL_Ext-062 | RDC
MC_AGL_Ext-064 | RDC
MC_AGL_Ext-058 | RDC
MC_AGL_Ext-059 | RDC
MC_AGL_Ext-060 | RDC
MC_AGL_Ext-061 | RDC
MC_AGL_Ext-038 | RDC
MC_AGL_Ext-017 | R+1
MC_AGL_Ext-019 | R+1
MC_AGL_Ext-020 | R+1
MC_AGL_Ext-021 | R+1
MC_AGL_Ext-018 | R+1
MC_AGL_Ext-022 | R+1
MC_AGL_Ext-024 | R+1
MC_AGL_Ext-025 | R+1
MC_AGL_Ext-023 | R+1
MC_AGL_Ext-026 | R+1
2 x MC_AGL_Ext-040 | R+1
MC_AGL_Ext-042 | R+1
MC_AGL_Ext-041 | R+1
MC_AGL_Ext-044 | R+1
MC_AGL_Ext-043 | R+1
2 x MC_AGL_Ext-046 | R+1
2 x MC_AGL_Ext-045 | R+1
2 x MC_AGL_Ext-047 | R+1
2 x MC_AGL_Ext-049 | R+1
2 x MC_AGL_Ext-050 | R+1
2 x MC_AGL_Ext-048 | R+1
2 x MC_AGL_Ext-051 | R+1
2 x MC_AGL_Ext-053 | R+1
2 x MC_AGL_Ext-052 | R+1
2 x MC_AGL_Ext-054 | R+1
2 x MC_AGL_Ext-057 | R+1
2 x MC_AGL_Ext-055 | R+1
2 x MC_AGL_Ext-056 | R+1
MC_AGL_Ext-058 | R+1
MC_AGL_Ext-059 | R+1
MC_AGL_Ext-060 | R+1
MC_AGL_Ext-060 | Combles
MC_AGL_Ext-042 | Combles
MC_AGL_Ext-043 | Combles
MC_AGL_Ext-044 | Combles
3 x MC_AGL_Ext-050 | Combles
2 x MC_AGL_Ext-052 | Combles
2 x MC_AGL_Ext-053 | Combles
2 x MC_AGL_Ext-051 | Combles
2 x MC_AGL_Ext-054 | Combles
2 x MC_AGL_Ext-055 | Combles
2 x MC_AGL_Ext-056 | Combles
2 x MC_AGL_Ext-057 | Combles
MC_AGL_Ext-017 | Combles
MC_AGL_Ext-018 | Combles
MC_AGL_Ext-041 | Combles
MC_AGL_Ext-019 | Combles
MC_AGL_Ext-021 | Combles
MC_AGL_Ext-022 | Combles
MC_AGL_Ext-020 | Combles
MC_AGL_Ext-023 | Combles
MC_AGL_Ext-025 | Combles
2 x MC_AGL_Ext-049 | Combles
2 x MC_AGL_Ext-045 | Combles
2 x MC_AGL_Ext-046 | Combles
2 x MC_AGL_Ext-048 | Combles
2 x MC_AGL_Ext-047 | Combles
2 x MC_AGL_Ext-040 | Combles
MC_AGL_Ext-026 | Combles
MC_AGL_Ext-024 | Combles
MC_AGL_Ext-058 | Combles
MC_AGL_Ext-059 | Combles

# IfcWallStandardCase: *PLAQUE DE PLATRE - CLOISON 13 (3)
Material: *PLAQUE DE PLATRE - CLOISON 0.013 m
AC_Pset_RenovationAndPhasing - Renovation Status: New
Name | In | IsExternal = LoadBearing
2 x Plaque de plâtre collée | RDC | yes
Plaque de plâtre collée | R+1 | no

# IfcWallStandardCase: *PLAQUE DE PLATRE - CLOISON 80 (55)
Material: *PLAQUE DE PLATRE - CLOISON 0.08 m
Pset_WallCommon - IsExternal: yes; LoadBearing: yes
AC_Pset_RenovationAndPhasing - Renovation Status: New
Name | In
29 x Cloison modulaire | RDC
26 x Cloison modulaire | R+1

# IfcWallStandardCase: 3.0-Refend: béton + enduit plâtre 2 faces 210 (4)
In: RDC
Material: Finition int - Enduit plâtre 0.015 m, Struct. - B.A. banché 0.18 m, Finition int - Enduit plâtre 0.015 m
AC_Pset_RenovationAndPhasing - Renovation Status: New
Pset_WallCommon - IsExternal: yes; LoadBearing: yes
Name
Cloisons ép. 74mm
Cloisons ép. 73mm
Cloisons ép. 72mm
Cloisons ép. 75mm

# IfcWallStandardCase: Béton 200 (5)
Material: Béton 0.2 m
Pset_WallCommon - IsExternal: yes; LoadBearing: yes
AC_Pset_RenovationAndPhasing - Renovation Status: New
Name | In
MC_AGL_Ext-059 | R-1
MC_AGL_Ext-057 | R-1
MC_AGL_Ext-056 | R-1
MC_AGL_Ext-058 | R-1
MC_AGL_Ext-056 | RDC

# IfcWallStandardCase: MANQUANT 50, MUR 01
In: RDC
Material: MANQUANT 0.05 m
AC_Pset_RenovationAndPhasing - Renovation Status: New
Pset_WallCommon - IsExternal: yes; LoadBearing: yes

# IfcWallStandardCase: Métal - Fer 10 (6)
Material: Métal - Fer 0.01 m
Pset_WallCommon - IsExternal: yes; LoadBearing: yes
Name | In | Renovation Status
2 x MC_AGL_Ext-061 | RDC | Existing
3 x MC_AGL_Ext-062 | Toiture | Existing
MC_AGL_Ext-062 | Toiture | New

# IfcWindow: Fenêtre 27 (3)
In: RDC
Type - OperationType: DOUBLE_PANEL_HORIZONTAL; ParameterTakesPrecedence: no; Sizeable: no
Type - Window Lining Properties - LiningDepth: 0.16 m; LiningThickness: 0.05 m; TransomThickness: 0.05 m; FirstTransomOffset: 0.347826
Type - Window Panel Properties - Panel 1 - OperationType: TILTANDTURNRIGHTHAND; PanelPosition: TOP; FrameDepth: 0.05 m; FrameThickness: 0.05 m
Type - Window Panel Properties - Panel 2 - OperationType: FIXEDCASEMENT; PanelPosition: BOTTOM
OverallHeight: 2.3 m; OverallWidth: 0.9 m
Pset_WindowCommon - ThermalTransmittance: 0; GlazingAreaFraction: 1.5725; IsExternal: yes
AC_Pset_RenovationAndPhasing - Renovation Status: New

# IfcWindow: Fenêtre 27 (46)
Type - OperationType: SINGLE_PANEL; ParameterTakesPrecedence: no; Sizeable: no
Type - Window Lining Properties - LiningDepth: 0.08 m; LiningThickness: 0.05 m
Type - Window Panel Properties - Panel 1 - OperationType: FIXEDCASEMENT; PanelPosition: MIDDLE
OverallHeight: 2.6 m
Pset_WindowCommon - ThermalTransmittance: 0
AC_Pset_RenovationAndPhasing - Renovation Status: New
Name | In | OverallWidth (m) | GlazingAreaFraction | IsExternal
PC.01b | RDC | 2.063 | 4.9075 | yes
3 x CH.3+vitrophanie | RDC | 1.347 | 3.1175 | yes
21 x CH.1+vitrophanie | RDC | 0.9 | 2 | yes
2 x CH.2+vitrophanie | RDC | 0.44 | 0.85 | yes
16 x CH.1+vitrophanie | R+1 | 0.9 | 2 | no
3 x CH.2+vitrophanie | R+1 | 0.44 | 0.85 | no

# IfcWindow: Fenêtre 27 (22)
Type - OperationType: SINGLE_PANEL; ParameterTakesPrecedence: no; Sizeable: no
Type - Window Lining Properties - LiningDepth: 0.16 m; LiningThickness: 0.05 m
Type - Window Panel Properties - Panel 1 - OperationType: TILTANDTURNLEFTHAND; PanelPosition: MIDDLE; FrameDepth: 0.05 m; FrameThickness: 0.05 m
OverallHeight: 1.5 m
Pset_WindowCommon - ThermalTransmittance: 0; IsExternal: yes
AC_Pset_RenovationAndPhasing - Renovation Status: New
Name | In | OverallWidth (m) | GlazingAreaFraction
11 x ME.01 | RDC | 0.9 | 1.0125
9 x ME.05 | R+1 | 0.9 | 1.0125
2 x ME.07 | R+1 | 1.05 | 1.215

# IfcWindow: Fenêtre 27 (33)
Type - OperationType: SINGLE_PANEL; ParameterTakesPrecedence: no; Sizeable: no
Type - Window Lining Properties - LiningDepth: 0.16 m; LiningThickness: 0.05 m
Type - Window Panel Properties - Panel 1 - OperationType: TILTANDTURNRIGHTHAND; PanelPosition: MIDDLE; FrameDepth: 0.05 m; FrameThickness: 0.05 m
OverallHeight: 1.5 m; OverallWidth: 0.9 m
Pset_WindowCommon - ThermalTransmittance: 0; GlazingAreaFraction: 1.0125; IsExternal: yes
AC_Pset_RenovationAndPhasing - Renovation Status: New
Name | In
18 x ME.01 | RDC
15 x ME.05 | R+1

# IfcWindow: Fenêtre double 27, ME.03
In: R+1
Type - OperationType: DOUBLE_PANEL_VERTICAL; ParameterTakesPrecedence: no; Sizeable: no
Type - Window Lining Properties - LiningDepth: 0.16 m; LiningThickness: 0.05 m; MullionThickness: 0.05 m; FirstMullionOffset: 0.515625
Type - Window Panel Properties - Panel 1 - OperationType: TILTANDTURNRIGHTHAND; PanelPosition: LEFT; FrameDepth: 0.05 m; FrameThickness: 0.05 m
Type - Window Panel Properties - Panel 2 - OperationType: FIXEDCASEMENT; PanelPosition: RIGHT
OverallHeight: 1.5 m; OverallWidth: 1.6 m
Pset_WindowCommon - ThermalTransmittance: 0; GlazingAreaFraction: 1.85625; IsExternal: yes
AC_Pset_RenovationAndPhasing - Renovation Status: New

# IfcWindow: Fenêtre horizontale à châssis multiples 27 (2)
Type - OperationType: USERDEFINED; ParameterTakesPrecedence: no; Sizeable: no
OverallHeight: 1.5 m; OverallWidth: 3.028 m
Pset_WindowCommon - ThermalTransmittance: 0; GlazingAreaFraction: 3.476; IsExternal: yes
AC_Pset_RenovationAndPhasing - Renovation Status: New
Name | In
ME.04 | RDC
ME.06 | R+1

# IfcWindow: Lanterneau plat 27, WC PMR
In: Combles
Type - ParameterTakesPrecedence: no; Sizeable: no
AC_Pset_RenovationAndPhasing - Renovation Status: New
